VERSION 5.7 ;
  NOWIREEXTENSIONATPIN ON ;
  DIVIDERCHAR "/" ;
  BUSBITCHARS "[]" ;
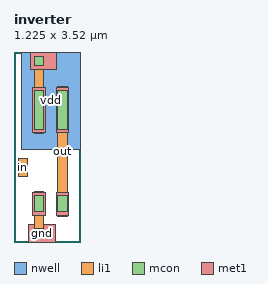
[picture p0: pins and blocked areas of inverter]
MACRO inverter
  CLASS BLOCK ;
  FOREIGN inverter ;
  ORIGIN 0.305 0.670 ;
  SIZE 1.225 BY 3.520 ;
  PIN vdd
    ANTENNADIFFAREA 0.270800 ;
    PORT
      LAYER nwell ;
        RECT -0.170 1.050 0.920 2.850 ;
      LAYER li1 ;
        RECT 0.070 1.340 0.240 2.780 ;
      LAYER mcon ;
        RECT 0.070 2.605 0.240 2.775 ;
        RECT 0.070 1.420 0.240 2.140 ;
      LAYER met1 ;
        RECT -0.005 2.530 0.490 2.850 ;
        RECT 0.040 1.360 0.270 2.200 ;
    END
  END vdd
  PIN gnd
    ANTENNADIFFAREA 0.149000 ;
    PORT
      LAYER li1 ;
        RECT 0.070 -0.600 0.240 0.270 ;
      LAYER mcon ;
        RECT 0.070 -0.110 0.240 0.190 ;
        RECT 0.070 -0.595 0.240 -0.425 ;
      LAYER met1 ;
        RECT 0.040 -0.170 0.270 0.250 ;
        RECT -0.030 -0.670 0.460 -0.350 ;
    END
  END gnd
  PIN out
    ANTENNADIFFAREA 0.365400 ;
    PORT
      LAYER li1 ;
        RECT 0.510 -0.190 0.680 2.220 ;
      LAYER mcon ;
        RECT 0.510 1.420 0.680 2.140 ;
        RECT 0.510 -0.110 0.680 0.190 ;
      LAYER met1 ;
        RECT 0.480 1.360 0.710 2.200 ;
        RECT 0.480 -0.170 0.710 0.250 ;
    END
  END out
  PIN in
    ANTENNAGATEAREA 0.189000 ;
    PORT
      LAYER li1 ;
        RECT -0.225 0.545 -0.055 0.875 ;
    END
  END in
END inverter
END LIBRARY

